VERSION 5.8 ;
BUSBITCHARS "[]" ;
DIVIDERCHAR "/" ;
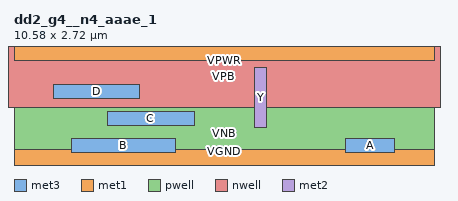
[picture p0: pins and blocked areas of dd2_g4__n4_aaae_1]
MACRO dd2_g4__n4_aaae_1
  CLASS CORE ;
  ORIGIN 0 0 ;
  SIZE 10.580 BY 2.720 ;
  SYMMETRY X Y ;
  SITE unithd ;
  PIN A
    DIRECTION INPUT ;
    USE SIGNAL ;
    ANTENNAGATEAREA 0.213000 ;
    PORT
      LAYER met3 ;
        RECT 8.345 0.175 9.595 0.505 ;
    END
  END A
  PIN B
    DIRECTION INPUT ;
    USE SIGNAL ;
    ANTENNAGATEAREA 0.213000 ;
    PORT
      LAYER met3 ;
        RECT 1.445 0.175 4.075 0.505 ;
    END
  END B
  PIN C
    DIRECTION INPUT ;
    USE SIGNAL ;
    ANTENNAGATEAREA 0.213000 ;
    PORT
      LAYER met3 ;
        RECT 2.365 0.855 4.535 1.185 ;
    END
  END C
  PIN D
    DIRECTION INPUT ;
    USE SIGNAL ;
    ANTENNAGATEAREA 0.213000 ;
    PORT
      LAYER met3 ;
        RECT 0.985 1.535 3.155 1.865 ;
    END
  END D
  PIN VGND
    DIRECTION INOUT ;
    USE GROUND ;
    SHAPE ABUTMENT ;
    PORT
      LAYER met1 ;
        RECT 0.000 -0.240 10.580 0.240 ;
    END
  END VGND
  PIN VNB
    DIRECTION INOUT ;
    USE GROUND ;
    PORT
      LAYER pwell ;
        RECT 0.000 0.000 10.580 1.305 ;
    END
  END VNB
  PIN VPB
    DIRECTION INOUT ;
    USE POWER ;
    PORT
      LAYER nwell ;
        RECT -0.190 1.305 10.770 2.910 ;
    END
  END VPB
  PIN VPWR
    DIRECTION INOUT ;
    USE POWER ;
    SHAPE ABUTMENT ;
    PORT
      LAYER met1 ;
        RECT 0.000 2.480 10.580 2.960 ;
    END
  END VPWR
  PIN Y
    DIRECTION OUTPUT ;
    USE SIGNAL ;
    ANTENNADIFFAREA 2.105800 ;
    PORT
      LAYER met2 ;
        RECT 6.050 0.790 6.370 2.305 ;
    END
  END Y
  OBS
    LAYER li1 ;
      RECT 0.000 -0.085 10.580 0.085 ;
      RECT 0.605 0.085 0.775 0.565 ;
      RECT 2.905 0.085 3.075 0.565 ;
      RECT 8.425 0.085 8.595 0.565 ;
      RECT 1.905 0.255 2.235 0.710 ;
      RECT 4.665 0.255 4.995 0.710 ;
      RECT 5.585 0.255 5.915 0.710 ;
      RECT 7.425 0.255 7.755 0.710 ;
      RECT 9.725 0.255 10.055 0.710 ;
      RECT 1.065 0.380 1.235 1.075 ;
      RECT 0.945 1.075 1.275 1.245 ;
      RECT 2.445 0.380 2.615 1.075 ;
      RECT 2.325 1.075 2.655 1.245 ;
      RECT 3.825 0.380 3.995 1.075 ;
      RECT 3.705 1.075 4.035 1.245 ;
      RECT 6.585 0.380 6.755 1.075 ;
      RECT 6.465 1.075 6.795 1.245 ;
      RECT 7.965 0.380 8.135 1.075 ;
      RECT 7.845 1.075 8.175 1.245 ;
      RECT 9.345 0.380 9.515 1.075 ;
      RECT 9.225 1.075 9.555 1.245 ;
      RECT 1.485 1.075 1.815 1.245 ;
      RECT 1.525 1.245 1.695 2.340 ;
      RECT 2.865 1.075 3.195 1.245 ;
      RECT 2.905 1.245 3.075 2.340 ;
      RECT 4.245 1.075 4.575 1.245 ;
      RECT 4.285 1.245 4.455 2.340 ;
      RECT 5.165 1.075 5.495 1.245 ;
      RECT 5.205 1.245 5.375 2.340 ;
      RECT 7.005 1.075 7.335 1.245 ;
      RECT 7.045 1.245 7.215 2.340 ;
      RECT 8.385 1.075 8.715 1.245 ;
      RECT 8.425 1.245 8.595 2.340 ;
      RECT 0.525 1.505 0.855 2.465 ;
      RECT 6.045 1.505 6.375 2.465 ;
      RECT 8.805 1.505 9.135 2.465 ;
      RECT 1.985 1.495 2.155 2.635 ;
      RECT 7.505 1.495 7.675 2.635 ;
      RECT 0.000 2.635 10.580 2.805 ;
    LAYER met1 ;
      RECT 1.005 0.380 1.295 0.710 ;
      RECT 1.905 0.380 2.235 0.710 ;
      RECT 2.385 0.380 2.675 0.710 ;
      RECT 3.765 0.380 4.055 0.710 ;
      RECT 4.665 0.380 4.995 0.710 ;
      RECT 6.525 0.380 6.815 0.710 ;
      RECT 7.425 0.380 7.755 0.710 ;
      RECT 7.905 0.380 8.195 0.710 ;
      RECT 9.285 0.380 9.575 0.710 ;
      RECT 9.725 0.380 10.055 0.710 ;
      RECT 5.585 0.380 5.915 0.710 ;
      RECT 5.590 0.710 5.910 0.850 ;
      RECT 6.050 0.790 6.370 0.850 ;
      RECT 5.585 0.850 6.375 0.990 ;
      RECT 5.590 0.990 5.910 1.050 ;
      RECT 6.050 0.990 6.370 1.050 ;
      RECT 6.510 1.230 6.830 1.290 ;
      RECT 6.970 1.230 7.290 1.290 ;
      RECT 8.810 1.230 9.130 1.290 ;
      RECT 9.730 1.230 10.050 1.290 ;
      RECT 6.505 1.290 10.055 1.430 ;
      RECT 6.510 1.430 6.830 1.490 ;
      RECT 6.970 1.430 7.290 1.490 ;
      RECT 8.810 1.430 9.130 1.490 ;
      RECT 9.730 1.430 10.050 1.490 ;
      RECT 1.465 2.010 1.755 2.340 ;
      RECT 2.845 2.010 3.135 2.340 ;
      RECT 4.225 2.010 4.515 2.340 ;
      RECT 0.530 1.670 0.850 1.730 ;
      RECT 4.670 1.670 4.990 1.730 ;
      RECT 5.130 1.670 5.450 1.730 ;
      RECT 7.890 1.670 8.210 1.730 ;
      RECT 0.525 1.730 8.215 1.870 ;
      RECT 4.670 1.870 4.990 1.930 ;
      RECT 5.130 1.870 5.450 1.930 ;
      RECT 7.890 1.870 8.210 1.930 ;
      RECT 0.530 1.870 0.850 2.010 ;
      RECT 5.135 1.930 5.445 2.175 ;
      RECT 0.525 2.010 0.855 2.340 ;
      RECT 5.145 2.175 5.435 2.340 ;
      RECT 6.045 2.010 6.375 2.340 ;
      RECT 6.985 2.010 7.275 2.340 ;
      RECT 8.365 2.010 8.655 2.340 ;
      RECT 8.805 2.010 9.135 2.340 ;
    LAYER met2 ;
      RECT 3.770 0.155 4.050 0.210 ;
      RECT 3.750 0.210 4.070 0.675 ;
      RECT 9.290 0.155 9.570 0.210 ;
      RECT 9.270 0.210 9.590 0.675 ;
      RECT 5.590 0.415 5.910 1.050 ;
      RECT 2.370 0.415 2.690 1.150 ;
      RECT 2.390 1.150 2.670 1.205 ;
      RECT 6.510 0.415 6.830 1.490 ;
      RECT 9.730 0.415 10.050 1.490 ;
      RECT 0.990 0.415 1.310 1.830 ;
      RECT 1.010 1.830 1.290 1.885 ;
      RECT 4.670 0.415 4.990 1.930 ;
      RECT 7.890 0.415 8.210 1.930 ;
      RECT 0.530 1.670 0.850 2.305 ;
      RECT 1.470 0.155 1.750 0.210 ;
      RECT 1.450 0.210 1.770 2.305 ;
      RECT 2.850 1.515 3.130 1.570 ;
      RECT 2.830 1.570 3.150 2.305 ;
      RECT 4.230 0.835 4.510 0.890 ;
      RECT 4.210 0.890 4.530 2.305 ;
      RECT 5.130 1.670 5.450 2.305 ;
      RECT 6.970 1.230 7.290 2.305 ;
      RECT 8.370 0.155 8.650 0.210 ;
      RECT 8.350 0.210 8.670 2.305 ;
      RECT 8.810 1.230 9.130 2.305 ;
      RECT 1.910 0.415 2.230 2.510 ;
      RECT 1.930 2.510 2.210 2.565 ;
      RECT 7.430 0.415 7.750 2.510 ;
      RECT 7.450 2.510 7.730 2.565 ;
    LAYER met3 ;
      RECT 1.905 2.215 7.755 2.545 ;
  END
END dd2_g4__n4_aaae_1
END LIBRARY
